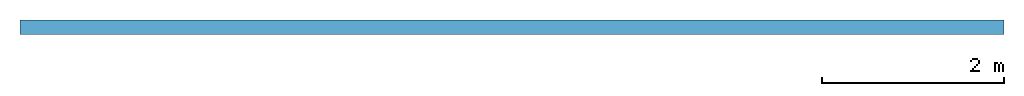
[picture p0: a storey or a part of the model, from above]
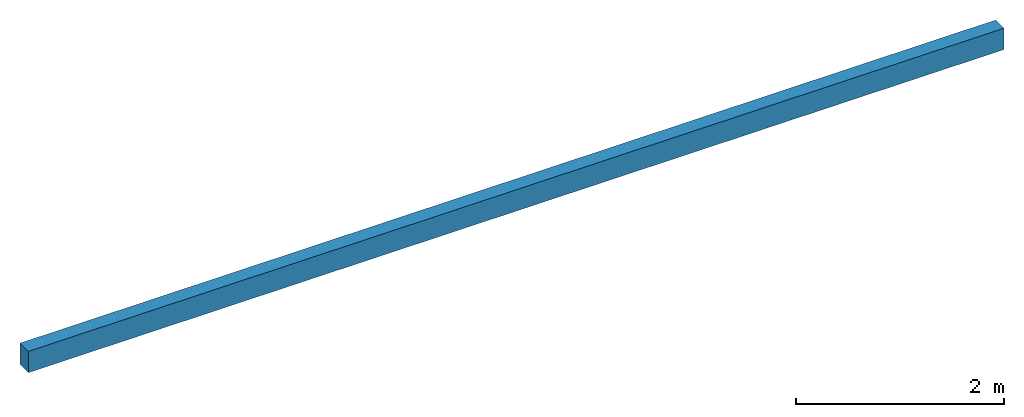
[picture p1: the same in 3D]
Properties of the parts of a building model (IFC2X3)

# File
Description: ViewDefinition [CoordinationView_V2.0, SpaceBoundary1stLevelAddOnView, SpaceBoundary2ndLevelAddOnView, QuantityTakeOffAddOnView], ExchangeRequirement[Architecture]
File name: /Users/Robert/___rob/gester/architecture_CMP/EXPORTS/IFC/20170117_CMPv2015_PW v2016 v2017_IFC2x3_po_komponentach.ifc
Time: 2017-01-03T18:41:15
Author: rob
Organization: abi
Written by: Vectorworks Architect 2017 SP2 (Build 338823) (64-Bit) by Vectorworks, Inc.
Made in: Macintosh

# IfcProject: Vectorworks, CMP_366
LongName: CMP_366; Phase: building permit

# IfcBuildingStorey, GroundFloor
Elevation: 0 mm

# IfcFireSuppressionTerminalType, no part of this type: IfcBuildingElementProxy
PredefinedType: FIREHYDRANT
